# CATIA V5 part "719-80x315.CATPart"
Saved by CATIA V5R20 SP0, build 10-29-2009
Part number: 719-80x315
Definition: NONE
Nomenclature: 719-80x315
Source: Unknown
Description: 719-80x315
Bounding box of the stored display mesh (mm): x 0 to 375, y -47.5 to 47.5, z -47.5 to 47.5
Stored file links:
  C:\Users\Utente\Desktop\IO LAVORO\3D X SITO CF\X SITO\719\719-80x315.CATPart

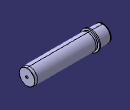
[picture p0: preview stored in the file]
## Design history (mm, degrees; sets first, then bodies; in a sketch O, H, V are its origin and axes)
Body1 "719-80x315" (main body)
  Solid1: solid without history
